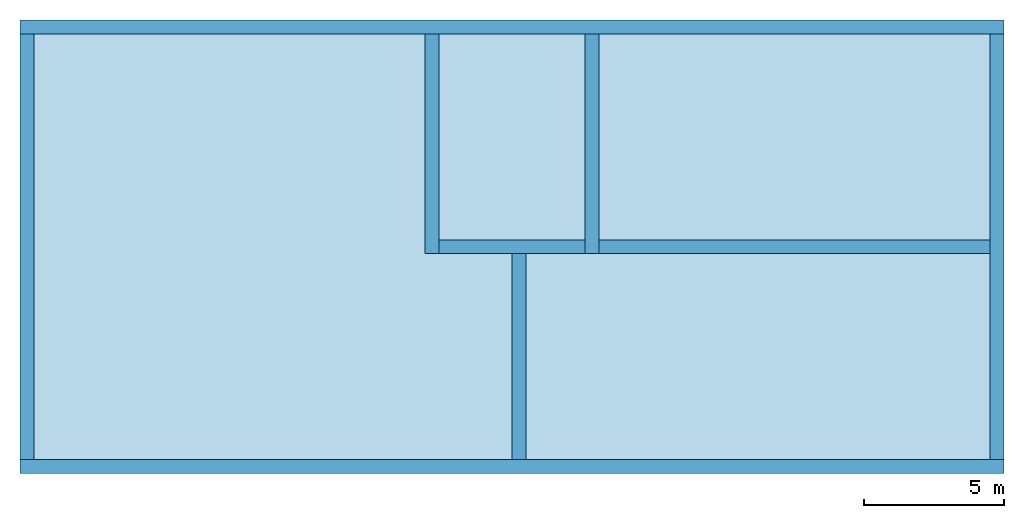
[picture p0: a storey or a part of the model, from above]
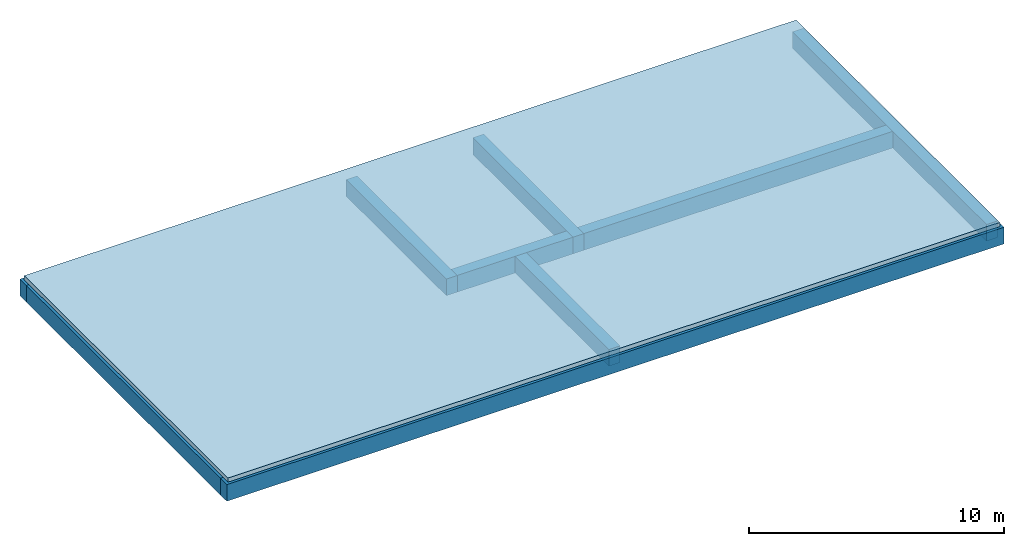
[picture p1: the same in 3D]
Properties of the parts of a building model (IFC4)

# File
Description: ViewDefinition[DesignTransferView]
File name: Bodenplatte-01.ifc
Time: 2023-08-26T18:34:02+02:00
Author: Böttcher, peter.boettcher@htwsaar.de
Organization: htw saar
Written by: IfcOpenShell v0.7.0-8f41ae0c1
Made in: BlenderBIM 0.0.230701
Authorization: Nobody

# IfcBeam (2)
In: 05 Dach
PredefinedType: BEAM; Material: Fichte
Name
Pfette links
Pfette rechts

# IfcBeam: Beton (9)
In: 01 Gruendung
Type - Material: C 25/30
EPset_Parametric - Engine: BlenderBIM.DumbProfile
Name
2 x Fundament 1
Fundament 1.002
Fundament 1.003
Fundament 2.001
Fundament 2.004
Fundament 2.003
Fundament 2.002
Fundament 2

# IfcBeam: Holzbalken (72)
In: 05 Dach
Type - Material: Fichte
EPset_Parametric - Engine: BlenderBIM.DumbProfile
Name
Sparren rechts | BBIM_Array - Data: [{"children": ["050581mj185gCgp_krlfUy", "2$ElHgglz83PE6LAPT95Bw", "0u$7DKgMz2aw_cnsl3YusA", "0zn2O1pVn8dhvzKyl2QHFT", "0A6$qVUUT4ivN9it$IFS3L", "2YOAN0E$XAo8DeTDdwaAe9", "206Nx5ct12uBUiV_EWX56b", "1r5az9xorAjh85aoiLjZPG", "2mbJ_Eamz8WgsDEFoJe0Za", "0L7u_xohPDnw2AS72pk46x", "1ADo55mkD8496dSpL$8tlL", "2w_FHJXRDALulF1shHy_vB", "0F3BB$WbnFp8l3dm0M6k1G", "2LtIGmfSP2rfd2xc9FUfDN", "2yEsjCmwnF1fjjMktjmIgw", "17PgFAjEP2aQHiwBc438Xk", "3TB8KBtj55sxQg16MDfFMt", "0ZeoJ73VP4lAcGQVxIq9YH", "2EuM_P6I5BoxbnVxcZMAuL", "2gNmZp4of7ygu32WlQn3Fo", "16TXRrJjrEWuI_7UjDAY0p", "3hGw48x7H13xoZmpF1PTRb", "10O6nJpLbBD8jW0y1TAfZ8", "0C6PzAGm52kOijvjRtIA7g", "3Mv9DhuH96Kvw$ZvmiJUEW", "3AjafHkQvE5gCYa32npaH1", "1eqroz00P5Sv24nE0o4Cyk", "3G9PcRzCL3wh2HW6buOZIf", "3FzM89SJj9QeOdhON$D0_x", "0ZtBm_MmL2BAS6775E6fTv", "2Zw1k5KibACgtU$_2xH_Wq", "2Sq1mXowD3TAjEdQm5bQk1", "0FdOthFfz3CxKDAYnhibzB", "2de3TI6E537wx_C716_a88", "3CIYw1buj4JRxfHf7drOeN"], "count": 36, "x": -0.9959999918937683, "y": 0.0, "z": 0.0, "use_local_space": true, "sync_children": false, "method": "OFFSET"}]
Sparren Links | BBIM_Array - Data: [{"children": ["1IQq4PCSL68xlh5VdA35Ey", "1FzK_yIiX05gTzA$_8$GWj", "2_DevLOYDFXe9CJt6o3JPO", "2ySCz5MM96G92irYZeDeNu", "150YTuQML81QXOKsOGUHaj", "3oFUOGVR92evs5umCiraJa", "2UC9yLL_n1muqIX6uCAoc8", "3XtXSm6$90QPfRLNS7GKDi", "12wrRXDLX36wtbxnLXKP6L", "2uDRpRR3bD1e6LJroN8Ncz", "3SKgnaCU9AgfJSSHxtx3DT", "1zl0YagsX0TPDD8UnsLzo9", "21zx_FSA96ZeblgaB908uC", "240Jbdp5n0rghrVW0GRBYt", "0RD7$dhOX1tQmLITdWD8wH", "3zc6CvwAL8xQCf$fWv1Lw4", "3_mT2TLlbDjguB$lu_y$8D", "0jfmtDs4DDNxL5jqWBsmS2", "2A5vR55_z3O9PztmPkSdXN", "3Cory4PIPDtAlEZ6QFR4bF", "0MfwcGHzXEROc5aJ37C96p", "2YIHv09yPEWxmxECz0hDXe", "35FPDyhdL0BPlsZXpRaM_F", "2RadfgZd93WRazpPLDLem_", "0ohjhWkQj0su63RaK3a6gq", "1$iXkG4vH9x8KNhMRnZgR7", "0XzFRPrI14XQlg6Edpt6WI", "0Qkb3IcMz848dbw6k7haUm", "2hrFao3vPA8O_2AlwLi2JK", "1EqitgbV90xQlUwOX2xvtt", "2EcSeW6yj12fLtglapXIWO", "0bI8rsKcL9IfyppFSYL8jH", "3CvKSzWCLEm9ZiYxFziuat", "0LClkWv69ETOxCK5tkkfHp", "3OsVT7QvrCChMY5h8buDTX"], "count": 36, "x": 0.9959999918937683, "y": 0.0, "z": 0.0, "use_local_space": true, "sync_children": false, "method": "OFFSET"}]
35 x Sparren rechts
35 x Sparren Links

# IfcBeam: Unterzug (2)
In: 02 Erdgeschoss
Type - Material: C 25/30
EPset_Parametric - Engine: BlenderBIM.DumbProfile
Name
Unterzug Halle
Unterzug Tor

# IfcRoof: Dacheindeckung (2)
In: 05 Dach
Type - Material: Dachziegel 0.05 m, Folie 0.01 m, Lattung 0.1 m
EPset_Parametric - Engine: BlenderBIM.DumbLayer3

# IfcSlab: Beton, Bodennplatte
In: 01 Gruendung
Type - Material: C 25/30 0.2 m
PredefinedType: BASESLAB
EPset_Parametric - Engine: BlenderBIM.DumbLayer3

# IfcSlab: Beton 25 cm (2)
Type - PredefinedType: FLOOR; Material: C 25/30 0.25 m
EPset_Parametric - Engine: BlenderBIM.DumbLayer3
Name | In
Decke über EG | 02 Erdgeschoss
Decke über OG | 03 Obergeschoss

# IfcSlab: Podestplatte
In: 02 Erdgeschoss
Type - Material: C 25/30 0.15 m
PredefinedType: LANDING
EPset_Parametric - Engine: BlenderBIM.DumbLayer3

# IfcWall: Beton (9)
Type - Material: C 25/30 0.2 m
EPset_Parametric - Engine: BlenderBIM.DumbLayer2
Name | In
5 x Treppenhaus | 02 Erdgeschoss
4 x Treppenhaus | 03 Obergeschoss

# IfcWall: Kalksandstein (24)
Type - PredefinedType: STANDARD; Material: Kalksandstein 0.24 m
EPset_Parametric - Engine: BlenderBIM.DumbLayer2
Name | In
8 x Wall | 02 Erdgeschoss
10 x Wall | 03 Obergeschoss
4 x Wall | 04 Dachgeschoss
2 x Giebelwand | 04 Dachgeschoss

# IfcWall: Trockenbau (3)
In: 02 Erdgeschoss
Type - Material: Gipskarton 0.1 m
EPset_Parametric - Engine: BlenderBIM.DumbLayer2
Name
Wall
2 x Trockenbau
